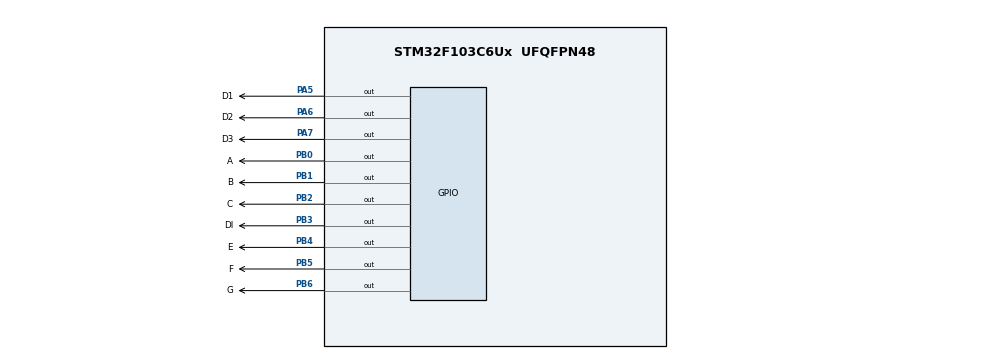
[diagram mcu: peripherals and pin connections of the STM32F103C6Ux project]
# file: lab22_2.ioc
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Mcu.Family=STM32F1
Mcu.Name=STM32F103C6Ux
Mcu.Package=UFQFPN48
NVIC.PriorityGroup=NVIC_PRIORITYGROUP_4
PA5.GPIO_Label=D1
PA5.Signal=GPIO_Output
PA6.GPIO_Label=D2
PA6.Signal=GPIO_Output
PA7.GPIO_Label=D3
PA7.Signal=GPIO_Output
PB0.GPIO_Label=A
PB0.Signal=GPIO_Output
PB1.GPIO_Label=B
PB1.Signal=GPIO_Output
PB2.GPIO_Label=C
PB2.Signal=GPIO_Output
PB3.GPIO_Label=DI
PB3.Signal=GPIO_Output
PB4.GPIO_Label=E
PB4.Signal=GPIO_Output
PB5.GPIO_Label=F
PB5.Signal=GPIO_Output
PB6.GPIO_Label=G
PB6.Signal=GPIO_Output
ProjectManager.HeapSize=0x200
ProjectManager.StackSize=0x400
ProjectManager.TargetToolchain=STM32CubeIDE
RCC.APB1Freq_Value=8000000
RCC.APB2Freq_Value=8000000
VP_SYS_VS_ND.Mode=No_Debug
board=custom

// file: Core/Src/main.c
/* USER CODE BEGIN Header */
/**
  ******************************************************************************
  * @file           : main.c
  * @brief          : Main program body
  ******************************************************************************
  * @attention
  *
  * <h2><center>&copy; Copyright (c) 2022 STMicroelectronics.
  * All rights reserved.</center></h2>
  *
  * This software component is licensed by ST under BSD 3-Clause license,
  * the "License"; You may not use this file except in compliance with the
  * License. You may obtain a copy of the License at:
  *                        opensource.org/licenses/BSD-3-Clause
  *
  ******************************************************************************
  */
/* USER CODE END Header */
#include "main.h"

void SystemClock_Config(void);
static void MX_GPIO_Init(void);

int main(void)
{

  /* MCU Configuration--------------------------------------------------------*/

  /* Reset of all peripherals, Initializes the Flash interface and the Systick. */
  HAL_Init();

  /* Configure the system clock */
  SystemClock_Config();

  /* Initialize all configured peripherals */
  MX_GPIO_Init();

  /* Infinite loop */
  /* USER CODE BEGIN WHILE */
  void display7SEG(int num){

	  if (num == 0)
	  {
		  HAL_GPIO_WritePin(GPIOB, A_Pin|B_Pin|C_Pin|DI_Pin|E_Pin|F_Pin, GPIO_PIN_RESET);
		  HAL_GPIO_WritePin(GPIOB, G_Pin, GPIO_PIN_SET);
	  }
	  else if (num == 1)
	  {
		  HAL_GPIO_WritePin(GPIOB, B_Pin|C_Pin, GPIO_PIN_RESET);
		  HAL_GPIO_WritePin(GPIOB, A_Pin|DI_Pin |E_Pin|F_Pin|G_Pin, GPIO_PIN_SET);
	  }
	  else if (num == 2)
	  {
		  HAL_GPIO_WritePin(GPIOB, A_Pin|B_Pin|DI_Pin|E_Pin|G_Pin, GPIO_PIN_RESET);
		  		  HAL_GPIO_WritePin(GPIOB, C_Pin|F_Pin, GPIO_PIN_SET);
	  }
	  else if (num == 3)
	  {
		  HAL_GPIO_WritePin(GPIOB, A_Pin|B_Pin|C_Pin|DI_Pin|G_Pin, GPIO_PIN_RESET);
		  		  HAL_GPIO_WritePin(GPIOB, E_Pin|F_Pin, GPIO_PIN_SET);
	  }
	  else if (num == 4)
	  {
		  HAL_GPIO_WritePin(GPIOB, B_Pin|C_Pin|F_Pin|G_Pin, GPIO_PIN_RESET);
		  HAL_GPIO_WritePin(GPIOB, E_Pin|A_Pin|DI_Pin, GPIO_PIN_SET);
	  }
	  else if (num == 5)
	  {
		  HAL_GPIO_WritePin(GPIOB, A_Pin|C_Pin|F_Pin|DI_Pin|G_Pin, GPIO_PIN_RESET);
		  		  HAL_GPIO_WritePin(GPIOB, E_Pin|B_Pin, GPIO_PIN_SET);
	  }
	  else if (num == 6)
	  {
		  HAL_GPIO_WritePin(GPIOB, A_Pin|C_Pin|F_Pin|E_Pin|DI_Pin|G_Pin, GPIO_PIN_RESET);
		  		  		  HAL_GPIO_WritePin(GPIOB, B_Pin, GPIO_PIN_SET);
	  }
	  else if (num == 7)
	  {
		  HAL_GPIO_WritePin(GPIOB, A_Pin|B_Pin|C_Pin, GPIO_PIN_RESET);
		  		  HAL_GPIO_WritePin(GPIOB, DI_Pin|E_Pin|F_Pin|G_Pin, GPIO_PIN_SET);
	  }
	  else if (num == 8)
	  {
		  HAL_GPIO_WritePin(GPIOB, A_Pin|B_Pin|C_Pin|DI_Pin|E_Pin|F_Pin|G_Pin, GPIO_PIN_RESET);
	  }
	  else if (num == 9)
	  {
		  HAL_GPIO_WritePin(GPIOB, A_Pin|B_Pin|C_Pin|DI_Pin
		                            |F_Pin|G_Pin, GPIO_PIN_RESET);
		  HAL_GPIO_WritePin(GPIOB,
		                            E_Pin, GPIO_PIN_SET);
	  }

//

  }
  int co =0;
  while (1)
  {
    /* USER CODE END WHILE */

	  if ( co >= 10) co = 0;
	   display7SEG (co++) ;

	   HAL_Delay (1000) ;
  }
}

void SystemClock_Config(void)
{
  RCC_OscInitTypeDef RCC_OscInitStruct = {0};
  RCC_ClkInitTypeDef RCC_ClkInitStruct = {0};

  /** Initializes the RCC Oscillators according to the specified parameters
  * in the RCC_OscInitTypeDef structure.
  */
  RCC_OscInitStruct.OscillatorType = RCC_OSCILLATORTYPE_HSI;
  RCC_OscInitStruct.HSIState = RCC_HSI_ON;
  RCC_OscInitStruct.HSICalibrationValue = RCC_HSICALIBRATION_DEFAULT;
  RCC_OscInitStruct.PLL.PLLState = RCC_PLL_NONE;
  if (HAL_RCC_OscConfig(&RCC_OscInitStruct) != HAL_OK)
  {
    Error_Handler();
  }
  /** Initializes the CPU, AHB and APB buses clocks
  */
  RCC_ClkInitStruct.ClockType = RCC_CLOCKTYPE_HCLK|RCC_CLOCKTYPE_SYSCLK
                              |RCC_CLOCKTYPE_PCLK1|RCC_CLOCKTYPE_PCLK2;
  RCC_ClkInitStruct.SYSCLKSource = RCC_SYSCLKSOURCE_HSI;
  RCC_ClkInitStruct.AHBCLKDivider = RCC_SYSCLK_DIV1;
  RCC_ClkInitStruct.APB1CLKDivider = RCC_HCLK_DIV1;
  RCC_ClkInitStruct.APB2CLKDivider = RCC_HCLK_DIV1;

  if (HAL_RCC_ClockConfig(&RCC_ClkInitStruct, FLASH_LATENCY_0) != HAL_OK)
  {
    Error_Handler();
  }
}

static void MX_GPIO_Init(void)
{
  GPIO_InitTypeDef GPIO_InitStruct = {0};

  /* GPIO Ports Clock Enable */
  __HAL_RCC_GPIOA_CLK_ENABLE();
  __HAL_RCC_GPIOB_CLK_ENABLE();

  /*Configure GPIO pin Output Level */
  HAL_GPIO_WritePin(GPIOA, D_Pin|V_Pin|X_Pin, GPIO_PIN_RESET);

  /*Configure GPIO pin Output Level */
  HAL_GPIO_WritePin(GPIOB, A_Pin|B_Pin|C_Pin|DI_Pin
                          |E_Pin|F_Pin|G_Pin, GPIO_PIN_RESET);

  /*Configure GPIO pins : D_Pin V_Pin X_Pin */
  GPIO_InitStruct.Pin = D_Pin|V_Pin|X_Pin;
  GPIO_InitStruct.Mode = GPIO_MODE_OUTPUT_PP;
  GPIO_InitStruct.Pull = GPIO_NOPULL;
  GPIO_InitStruct.Speed = GPIO_SPEED_FREQ_LOW;
  HAL_GPIO_Init(GPIOA, &GPIO_InitStruct);

  /*Configure GPIO pins : A_Pin B_Pin C_Pin DI_Pin
                           E_Pin F_Pin G_Pin */
  GPIO_InitStruct.Pin = A_Pin|B_Pin|C_Pin|DI_Pin
                          |E_Pin|F_Pin|G_Pin;
  GPIO_InitStruct.Mode = GPIO_MODE_OUTPUT_PP;
  GPIO_InitStruct.Pull = GPIO_NOPULL;
  GPIO_InitStruct.Speed = GPIO_SPEED_FREQ_LOW;
  HAL_GPIO_Init(GPIOB, &GPIO_InitStruct);

}

void Error_Handler(void)
{
  __disable_irq();
  while (1)
  {
  }
}

/************************ (C) COPYRIGHT STMicroelectronics *****END OF FILE****/
